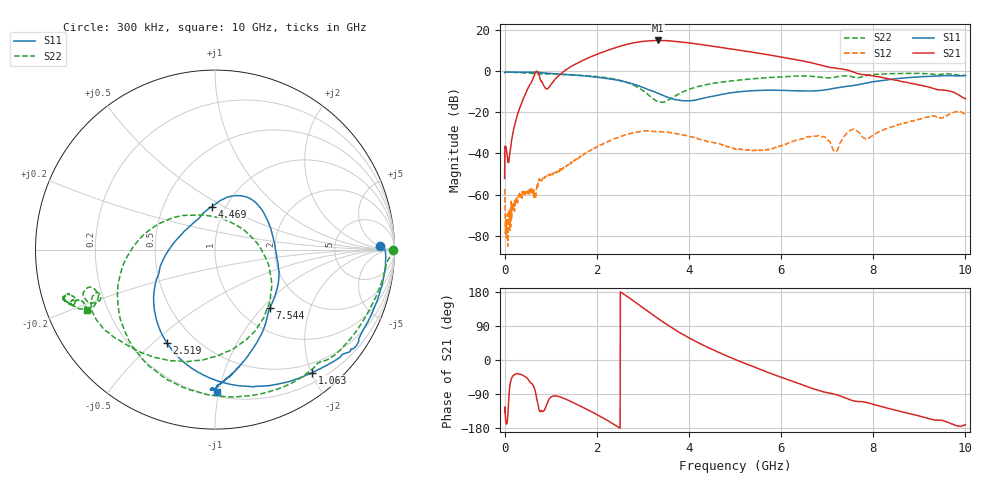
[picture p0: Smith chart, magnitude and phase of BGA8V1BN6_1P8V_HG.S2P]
!Agilent Technologies,E5071C,MY46316587,B.13.01
!Date: Tue Nov 28 12:40:46 2017
!Data & Calibration Information:
!Freq	S11:SOLT2(ON)	S21:SOLT2(ON)	S12:SOLT2(ON)	S22:SOLT2(ON)
!PortZ  Port1:50+j0  Port2:50+j0
!Above PortZ is port z conversion or system Z0 setting when saving the data.
!When reading, reference impedance value at option line is always used.
# Hz S dB R 50
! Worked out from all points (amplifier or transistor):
!   1601 points, 300 kHz to 10 GHz, reference 50 ohm
!   highest |S21| = 15.0 dB at 3.331 GHz (marker M1)
!   |S21| within 3 dB of that: 2.48 GHz to 4.588 GHz (2.109 GHz wide, 59.7 % of centre)
!   unconditionally stable (mu >= 1): start of sweep to end of sweep
!   at 1.663 GHz: K = 5.30, MAG = 12.8 dB, |S12| = -41.2 dB
!   at 5 GHz: K = 6.55, MAG = 13.0 dB, |S12| = -37.7 dB
!   at 10 GHz: K = 4.24, MAG = -5.3 dB, |S12| = -21.1 dB
!   lowest NFmin = 1.03 dB at 3.1 Hz
!   S11 on the Smith chart (normalised r, x): 300 kHz: 23, +7; 1.063 GHz: 0.35, -2.02; 2.519 GHz: 0.35, -0.56; 4.469 GHz: 0.86, +0.44; 7.544 GHz: 1.37, -1.10; 10 GHz: 0.23, -0.99
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300000  -0.71 1.4  -52.17 -136.7  -57.25 40.0  -0.06 -0.1
6.904794e7  -0.42 -3.4  -43.15 -147.2  -85.10 -173.9  -0.39 -5.8
2.877914e8  -0.45 -14.3  -20.46 -36.2  -61.97 106.0  -0.67 -20.5
6.565303e8  -0.51 -31.8  -1.32 -78.0  -60.05 117.0  -1.12 -44.1
7.627771e8  -0.66 -38.6  -3.00 -135.4  -52.82 129.2  -1.36 -48.7
1.062768e9  -1.17 -51.7  -4.80 -94.8  -49.45 124.2  -1.40 -66.1
1.669e9  -2.16 -77.4  5.00 -123.0  -40.93 139.1  -2.01 -100.5
2.131486e9  -3.23 -97.8  9.35 -152.5  -35.46 130.2  -2.92 -128.1
2.518974e9  -4.65 -117.1  12.24 179.2  -31.73 114.2  -4.47 -155.5
2.918962e9  -7.15 -141.1  14.29 145.4  -29.43 92.0  -8.17 165.2
3.33145e9  -10.75 -170.0  14.99 109.4  -29.32 68.8  -14.83 88.9
3.3377e9  -10.82 -170.6  14.99 108.8  -29.37 68.1  -14.87 87.0
3.593942e9  -13.07 166.0  14.75 87.7  -29.85 56.9  -13.52 21.4
3.906433e9  -14.38 134.5  14.06 64.7  -31.12 47.5  -9.71 -21.3
4.468916e9  -12.38 94.1  12.37 30.0  -34.46 42.9  -6.11 -61.6
5.00015e9  -10.21 74.0  10.59 1.5  -37.66 54.9  -4.50 -89.9
5.775127e9  -9.21 50.4  7.81 -35.4  -37.86 96.2  -3.02 -125.9
6.66885e9  -9.60 8.8  4.06 -74.6  -31.53 102.9  -2.46 -156.7
7.181335e9  -8.17 -24.5  1.53 -90.9  -38.89 112.5  -2.82 -155.9
7.543824e9  -7.02 -46.7  -0.15 -107.0  -28.36 122.5  -2.65 -163.4
8.33755e9  -4.03 -73.9  -3.68 -127.9  -27.57 136.3  -1.21 -160.1
1e10  -2.00 -89.3  -13.32 -170.4  -21.14 76.7  -2.06 -154.8
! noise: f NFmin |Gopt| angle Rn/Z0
3.1  1.031  0.2843  68.09  0.1664
3.2  1.066  0.2504  68.74  0.1647
3.3  1.1  0.219  71.25  0.162
3.4  1.142  0.2109  73.18  0.1591
3.5  1.17  0.1781  64.44  0.1721
3.6  1.198  0.1726  65.15  0.1625
3.7  1.212  0.1403  62.09  0.1614
3.8  1.258  0.1106  60.64  0.1644
3.9  1.284  0.08612  59.67  0.165
4  1.321  0.05983  63.84  0.1613
